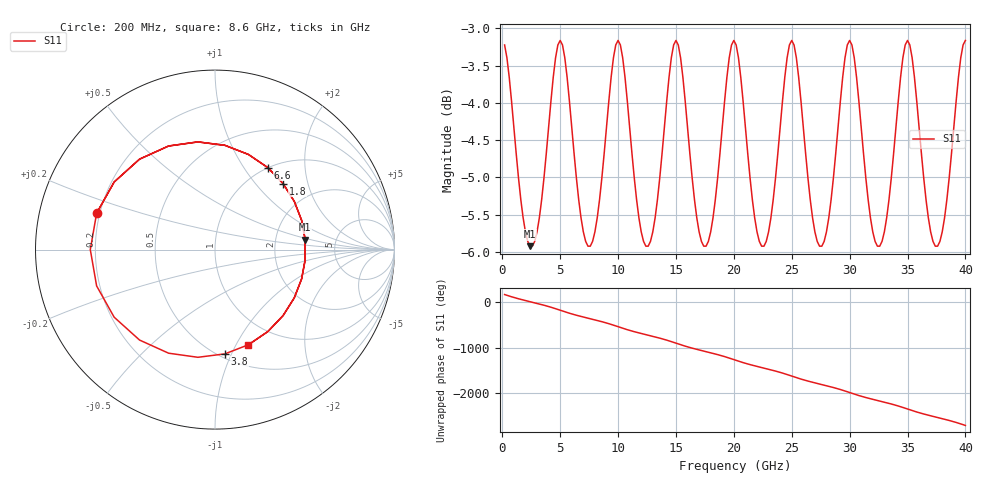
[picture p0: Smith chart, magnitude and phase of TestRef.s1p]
! File created by SignalIntegrity v1.5.2: Signal and Power Integrity Tools
! https://github.com/Nubis-Communications/SignalIntegrity
# MHz S MA R 50.0
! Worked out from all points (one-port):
!   200 points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, 200 MHz to 40 GHz, reference 50 ohm
!   lowest |S11| = -5.9 dB at 2.4 GHz (marker M1), VSWR 3.05, Z = 149 + j21.9 ohm
!   |S11| at or under -10 dB: nowhere
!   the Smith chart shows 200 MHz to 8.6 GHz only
!   S11 on the Smith chart (normalised r, x): 200 MHz: 0.19, +0.14; 1.8 GHz: 1.39, +1.41; 3.8 GHz: 0.54, -0.94; 6.6 GHz: 1.00, +1.29; 8.6 GHz: 0.73, -1.12
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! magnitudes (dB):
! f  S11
! 200 MHz  -3.2
! 1.8 GHz  -5.5
! 2.4 GHz  -5.9
! 3.8 GHz  -4.7
! 4.6 GHz  -3.4
! 5.2 GHz  -3.2
! 6.6 GHz  -5.3
! 7.6 GHz  -5.9
! 8.6 GHz  -5.0
! 9.6 GHz  -3.4
! 10.2 GHz  -3.2
! 12.4 GHz  -5.9
! 13.2 GHz  -5.5
! 14.6 GHz  -3.4
! 15.2 GHz  -3.2
! 17.4 GHz  -5.9
! 18.2 GHz  -5.5
! 19.6 GHz  -3.4
! 20.2 GHz  -3.2
! 22.4 GHz  -5.9
! 25.2 GHz  -3.2
! 27.4 GHz  -5.9
! 30.2 GHz  -3.2
! 32.4 GHz  -5.9
! 35.2 GHz  -3.2
! 36.8 GHz  -5.5
! 37.6 GHz  -5.9
! 40 GHz  -3.2
